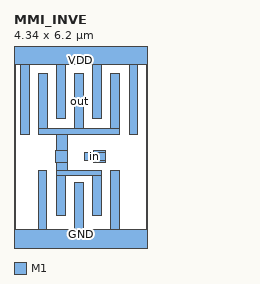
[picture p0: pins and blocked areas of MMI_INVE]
MACRO MMI_INVE
	CLASS CORE ;
	FOREIGN MMI_INVE 0 0 ;
	SIZE 4.34 BY 6.2 ;
	SYMMETRY X Y ;
	SITE CORE1 ;
	PIN out
		DIRECTION output ;
		USE SIGNAL ;
		PORT
			LAYER M1 ;
			RECT 0.805 3.695 1.085 5.49 ;
			LAYER M1 ;
			RECT 1.985 3.695 2.265 5.49 ;
			LAYER M1 ;
			RECT 3.165 3.695 3.445 5.49 ;
			LAYER M1 ;
			RECT 0.805 3.505 3.445 3.695 ;
			LAYER M1 ;
			RECT 1.375 2.98 1.74 3.505 ;
			LAYER M1 ;
			RECT 1.36 2.6 1.74 2.98 ;
			LAYER M1 ;
			RECT 1.375 2.345 1.74 2.6 ;
			LAYER M1 ;
			RECT 1.375 2.155 2.865 2.345 ;
			LAYER M1 ;
			RECT 1.385 0.875 1.665 2.155 ;
			LAYER M1 ;
			RECT 2.565 0.875 2.845 2.155 ;
		END
		AntennaDiffArea 4.0678 ;
	END out
	PIN GND
		DIRECTION inout ;
		USE GROUND ;
		PORT
			LAYER M1 ;
			RECT 0.795 0.42 1.075 2.345 ;
			LAYER M1 ;
			RECT 1.975 0.42 2.255 1.935 ;
			LAYER M1 ;
			RECT 3.155 0.42 3.435 2.345 ;
			LAYER M1 ;
			RECT 0 -0.42 4.34 0.42 ;
		END
	END GND
	PIN VDD
		DIRECTION inout ;
		USE POWER ;
		PORT
			LAYER M1 ;
			RECT 0 5.78 4.34 6.62 ;
			LAYER M1 ;
			RECT 0.215 3.505 0.495 5.78 ;
			LAYER M1 ;
			RECT 1.395 4.035 1.675 5.78 ;
			LAYER M1 ;
			RECT 2.575 4.035 2.855 5.78 ;
			LAYER M1 ;
			RECT 3.755 3.505 4.035 5.78 ;
		END
	END VDD
	PIN in
		DIRECTION input ;
		USE SIGNAL ;
		PORT
			LAYER M1 ;
			RECT 2.6 2.93 2.98 2.98 ;
			LAYER M1 ;
			RECT 2.29 2.65 2.98 2.93 ;
			LAYER M1 ;
			RECT 2.6 2.6 2.98 2.65 ;
		END
		AntennaGateArea 2.7735 ;
	END in
	OBS
	END
END MMI_INVE
